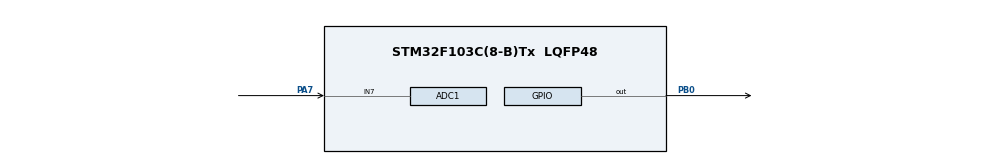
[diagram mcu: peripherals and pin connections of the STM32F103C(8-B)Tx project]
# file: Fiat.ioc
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ADC1.Channel-1\#ChannelRegularConversion=ADC_CHANNEL_7
ADC1.ContinuousConvMode=ENABLE
ADC1.NbrOfConversionFlag=1
ADC1.master=1
Mcu.Family=STM32F1
Mcu.Name=STM32F103C(8-B)Tx
Mcu.Package=LQFP48
NVIC.PriorityGroup=NVIC_PRIORITYGROUP_4
PA13.Mode=Serial_Wire
PA13.Signal=SYS_JTMS-SWDIO
PA14.Mode=Serial_Wire
PA14.Signal=SYS_JTCK-SWCLK
PA2.Signal=USART2_TX
PA7.Signal=ADCx_IN7
PB0.Signal=GPIO_Output
PD0-OSC_IN.Mode=HSE-External-Oscillator
PD0-OSC_IN.Signal=RCC_OSC_IN
PD1-OSC_OUT.Mode=HSE-External-Oscillator
PD1-OSC_OUT.Signal=RCC_OSC_OUT
ProjectManager.HeapSize=0x200
ProjectManager.StackSize=0x400
ProjectManager.TargetToolchain=STM32CubeIDE
RCC.APB1Freq_Value=8000000
RCC.APB2Freq_Value=8000000
SH.ADCx_IN7.0=ADC1_IN7,IN7
board=custom

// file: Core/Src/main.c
/* USER CODE BEGIN Header */
/**
  ******************************************************************************
  * @file           : main.c
  * @brief          : Main program body
  ******************************************************************************
  * @attention
  *
  * <h2><center>&copy; Copyright (c) 2019 STMicroelectronics.
  * All rights reserved.</center></h2>
  *
  * This software component is licensed by ST under BSD 3-Clause license,
  * the "License"; You may not use this file except in compliance with the
  * License. You may obtain a copy of the License at:
  *                        opensource.org/licenses/BSD-3-Clause
  *
  ******************************************************************************
  */
/* USER CODE END Header */

#include "main.h"

ADC_HandleTypeDef hadc1;

void SystemClock_Config(void);
static void MX_GPIO_Init(void);
static void MX_ADC1_Init(void);

int main(void)
{
  /* USER CODE BEGIN 1 */

	float vel_pedal = 0;
	uint16_t rawValue = 0;
  /* USER CODE END 1 */

  /* MCU Configuration--------------------------------------------------------*/

  /* Reset of all peripherals, Initializes the Flash interface and the Systick. */
  HAL_Init();

  /* Configure the system clock */
  SystemClock_Config();

  /* Initialize all configured peripherals */
  MX_GPIO_Init();
  MX_ADC1_Init();
  /* USER CODE BEGIN 2 */
  HAL_ADC_Start(&hadc1);
  /* USER CODE END 2 */

  /* Infinite loop */
  /* USER CODE BEGIN WHILE */
  while (1)
  {

	  //HAL_ADC_PollForConversion(&hadc1, 500);

	  rawValue = HAL_ADC_GetValue(&hadc1);

	  //relative pedal position from 0 to 100
	  vel_pedal=((float)rawValue)/4095*100;

	  //code for validation purposes
	  if(vel_pedal > 50)
		  HAL_GPIO_WritePin(GPIOB, GPIO_PIN_0, GPIO_PIN_SET);
	  else
		  HAL_GPIO_WritePin(GPIOB, GPIO_PIN_0, GPIO_PIN_RESET);

    /* USER CODE END WHILE */

  }
}

void SystemClock_Config(void)
{
  RCC_OscInitTypeDef RCC_OscInitStruct = {0};
  RCC_ClkInitTypeDef RCC_ClkInitStruct = {0};
  RCC_PeriphCLKInitTypeDef PeriphClkInit = {0};

  /** Initializes the CPU, AHB and APB busses clocks
  */
  RCC_OscInitStruct.OscillatorType = RCC_OSCILLATORTYPE_HSI;
  RCC_OscInitStruct.HSIState = RCC_HSI_ON;
  RCC_OscInitStruct.HSICalibrationValue = RCC_HSICALIBRATION_DEFAULT;
  RCC_OscInitStruct.PLL.PLLState = RCC_PLL_NONE;
  if (HAL_RCC_OscConfig(&RCC_OscInitStruct) != HAL_OK)
  {
    Error_Handler();
  }
  /** Initializes the CPU, AHB and APB busses clocks
  */
  RCC_ClkInitStruct.ClockType = RCC_CLOCKTYPE_HCLK|RCC_CLOCKTYPE_SYSCLK
                              |RCC_CLOCKTYPE_PCLK1|RCC_CLOCKTYPE_PCLK2;
  RCC_ClkInitStruct.SYSCLKSource = RCC_SYSCLKSOURCE_HSI;
  RCC_ClkInitStruct.AHBCLKDivider = RCC_SYSCLK_DIV1;
  RCC_ClkInitStruct.APB1CLKDivider = RCC_HCLK_DIV1;
  RCC_ClkInitStruct.APB2CLKDivider = RCC_HCLK_DIV1;

  if (HAL_RCC_ClockConfig(&RCC_ClkInitStruct, FLASH_LATENCY_0) != HAL_OK)
  {
    Error_Handler();
  }
  PeriphClkInit.PeriphClockSelection = RCC_PERIPHCLK_ADC;
  PeriphClkInit.AdcClockSelection = RCC_ADCPCLK2_DIV2;
  if (HAL_RCCEx_PeriphCLKConfig(&PeriphClkInit) != HAL_OK)
  {
    Error_Handler();
  }
}

static void MX_ADC1_Init(void)
{

  ADC_ChannelConfTypeDef sConfig = {0};

  /** Common config
  */
  hadc1.Instance = ADC1;
  hadc1.Init.ScanConvMode = ADC_SCAN_DISABLE;
  hadc1.Init.ContinuousConvMode = ENABLE;
  hadc1.Init.DiscontinuousConvMode = DISABLE;
  hadc1.Init.ExternalTrigConv = ADC_SOFTWARE_START;
  hadc1.Init.DataAlign = ADC_DATAALIGN_RIGHT;
  hadc1.Init.NbrOfConversion = 1;
  if (HAL_ADC_Init(&hadc1) != HAL_OK)
  {
    Error_Handler();
  }
  /** Configure Regular Channel
  */
  sConfig.Channel = ADC_CHANNEL_7;
  sConfig.Rank = ADC_REGULAR_RANK_1;
  sConfig.SamplingTime = ADC_SAMPLETIME_1CYCLE_5;
  if (HAL_ADC_ConfigChannel(&hadc1, &sConfig) != HAL_OK)
  {
    Error_Handler();
  }

}

static void MX_GPIO_Init(void)
{
  GPIO_InitTypeDef GPIO_InitStruct = {0};

  /* GPIO Ports Clock Enable */
  __HAL_RCC_GPIOD_CLK_ENABLE();
  __HAL_RCC_GPIOA_CLK_ENABLE();
  __HAL_RCC_GPIOB_CLK_ENABLE();

  /*Configure GPIO pin Output Level */
  HAL_GPIO_WritePin(GPIOB, GPIO_PIN_0, GPIO_PIN_RESET);

  /*Configure GPIO pin : PA2 */
  GPIO_InitStruct.Pin = GPIO_PIN_2;
  GPIO_InitStruct.Mode = GPIO_MODE_AF_PP;
  GPIO_InitStruct.Speed = GPIO_SPEED_FREQ_HIGH;
  HAL_GPIO_Init(GPIOA, &GPIO_InitStruct);

  /*Configure GPIO pin : PB0 */
  GPIO_InitStruct.Pin = GPIO_PIN_0;
  GPIO_InitStruct.Mode = GPIO_MODE_OUTPUT_PP;
  GPIO_InitStruct.Pull = GPIO_NOPULL;
  GPIO_InitStruct.Speed = GPIO_SPEED_FREQ_LOW;
  HAL_GPIO_Init(GPIOB, &GPIO_InitStruct);

}

void Error_Handler(void)
{
}

/************************ (C) COPYRIGHT STMicroelectronics *****END OF FILE****/
